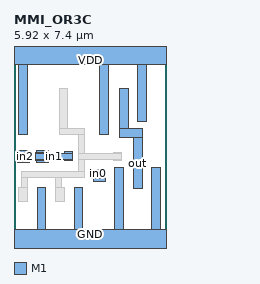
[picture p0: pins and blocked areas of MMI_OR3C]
MACRO MMI_OR3C
	CLASS CORE ;
	FOREIGN MMI_OR3C 0 0 ;
	SIZE 5.92 BY 7.4 ;
	SYMMETRY X Y ;
	SITE CORE1 ;
	PIN out
		DIRECTION output ;
		USE SIGNAL ;
		PORT
			LAYER M1 ;
			RECT 4.105 4.405 4.445 5.96 ;
			LAYER M1 ;
			RECT 4.105 4.065 4.99 4.405 ;
			LAYER M1 ;
			RECT 4.65 2.065 4.99 4.065 ;
		END
		AntennaDiffArea 1.4904 ;
	END out
	PIN in1
		DIRECTION input ;
		USE SIGNAL ;
		PORT
			LAYER M1 ;
			RECT 0.885 3.5 1.335 3.555 ;
			LAYER M1 ;
			RECT 0.85 3.445 1.335 3.5 ;
			LAYER M1 ;
			RECT 1.95 3.445 2.29 3.51 ;
			LAYER M1 ;
			RECT 0.85 3.215 2.29 3.445 ;
			LAYER M1 ;
			RECT 0.85 3.16 1.335 3.215 ;
			LAYER M1 ;
			RECT 1.95 3.17 2.29 3.215 ;
			LAYER M1 ;
			RECT 0.885 3.105 1.335 3.16 ;
		END
		AntennaGateArea 0.7812 ;
	END in1
	PIN GND
		DIRECTION inout ;
		USE GROUND ;
		PORT
			LAYER M1 ;
			RECT 0.9 0.5 1.24 2.125 ;
			LAYER M1 ;
			RECT 2.34 0.5 2.68 2.125 ;
			LAYER M1 ;
			RECT 3.93 0.5 4.27 2.905 ;
			LAYER M1 ;
			RECT 5.37 0.5 5.71 2.905 ;
			LAYER M1 ;
			RECT 0 -0.5 5.92 0.5 ;
		END
	END GND
	PIN in2
		DIRECTION input ;
		USE SIGNAL ;
		PORT
			LAYER M1 ;
			RECT 0.145 3.5 0.595 3.555 ;
			LAYER M1 ;
			RECT 0.12 3.16 0.595 3.5 ;
			LAYER M1 ;
			RECT 0.145 3.105 0.595 3.16 ;
		END
		AntennaGateArea 0.7812 ;
	END in2
	PIN VDD
		DIRECTION inout ;
		USE POWER ;
		PORT
			LAYER M1 ;
			RECT 4.825 7.9 5.165 7.92 ;
			LAYER M1 ;
			RECT 0 6.9 5.92 7.9 ;
			LAYER M1 ;
			RECT 0.18 4.18 0.52 6.9 ;
			LAYER M1 ;
			RECT 3.34 4.18 3.68 6.9 ;
			LAYER M1 ;
			RECT 4.825 4.68 5.165 6.9 ;
		END
	END VDD
	PIN in0
		DIRECTION input ;
		USE SIGNAL ;
		PORT
			LAYER M1 ;
			RECT 2.98 2.815 3.32 2.83 ;
			LAYER M1 ;
			RECT 2.98 2.49 3.555 2.815 ;
			LAYER M1 ;
			RECT 3.105 2.365 3.555 2.49 ;
		END
		AntennaGateArea 0.7812 ;
	END in0
	OBS
		LAYER M1 ;
		RECT 1.76 4.41 2.1 5.96 ;
		LAYER M1 ;
		RECT 1.76 4.18 2.75 4.41 ;
		LAYER M1 ;
		RECT 2.52 3.445 2.75 4.18 ;
		LAYER M1 ;
		RECT 3.865 3.445 4.205 3.5 ;
		LAYER M1 ;
		RECT 2.52 3.215 4.205 3.445 ;
		LAYER M1 ;
		RECT 2.52 2.755 2.75 3.215 ;
		LAYER M1 ;
		RECT 3.865 3.16 4.205 3.215 ;
		LAYER M1 ;
		RECT 0.29 2.525 2.75 2.755 ;
		LAYER M1 ;
		RECT 0.29 2.125 0.52 2.525 ;
		LAYER M1 ;
		RECT 1.62 2.125 1.85 2.525 ;
		LAYER M1 ;
		RECT 0.18 1.585 0.52 2.125 ;
		LAYER M1 ;
		RECT 1.62 1.585 1.96 2.125 ;
	END
END MMI_OR3C
